VERSION 5.7 ;
  NAMESCASESENSITIVE ON ;
  NOWIREEXTENSIONATPIN ON ;
  DIVIDERCHAR "/" ;
  BUSBITCHARS "[]" ;
UNITS
  DATABASE MICRONS 200 ;
END UNITS

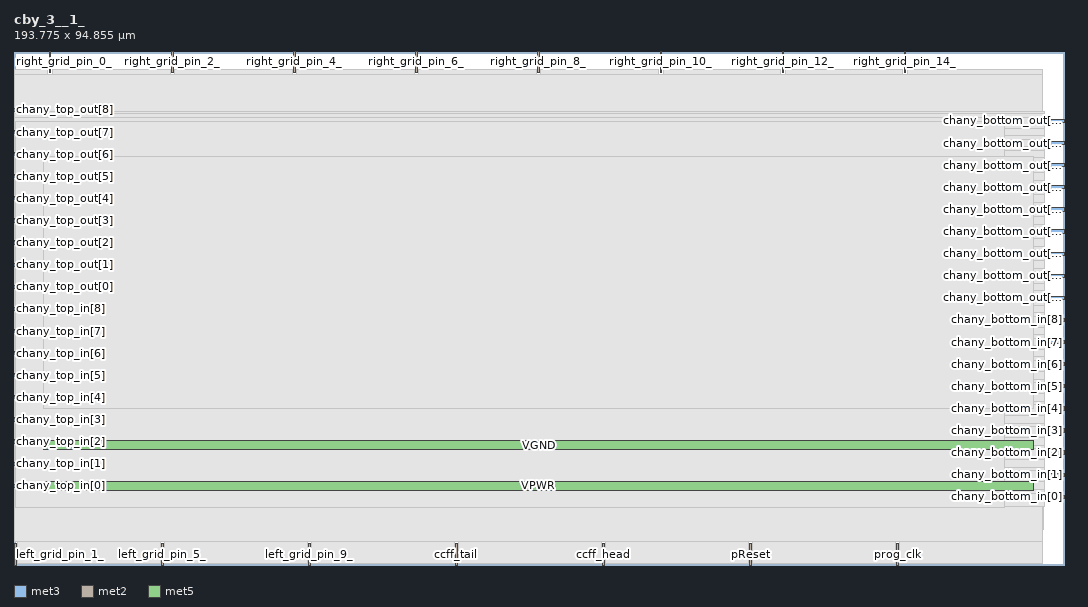
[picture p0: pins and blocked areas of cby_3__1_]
MACRO cby_3__1_
  CLASS BLOCK ;
  FOREIGN cby_3__1_ ;
  ORIGIN 0.000 0.000 ;
  SIZE 193.775 BY 94.855 ;
  PIN chany_top_in[0]
    DIRECTION INPUT ;
    PORT
      LAYER met3 ;
        RECT 0.000 14.320 4.000 14.920 ;
    END
  END chany_top_in[0]
  PIN chany_top_in[1]
    DIRECTION INPUT ;
    PORT
      LAYER met3 ;
        RECT 0.000 18.400 4.000 19.000 ;
    END
  END chany_top_in[1]
  PIN chany_top_in[2]
    DIRECTION INPUT ;
    PORT
      LAYER met3 ;
        RECT 0.000 22.480 4.000 23.080 ;
    END
  END chany_top_in[2]
  PIN chany_top_in[3]
    DIRECTION INPUT ;
    PORT
      LAYER met3 ;
        RECT 0.000 26.560 4.000 27.160 ;
    END
  END chany_top_in[3]
  PIN chany_top_in[4]
    DIRECTION INPUT ;
    PORT
      LAYER met3 ;
        RECT 0.000 30.640 4.000 31.240 ;
    END
  END chany_top_in[4]
  PIN chany_top_in[5]
    DIRECTION INPUT ;
    PORT
      LAYER met3 ;
        RECT 0.000 34.720 4.000 35.320 ;
    END
  END chany_top_in[5]
  PIN chany_top_in[6]
    DIRECTION INPUT ;
    PORT
      LAYER met3 ;
        RECT 0.000 38.800 4.000 39.400 ;
    END
  END chany_top_in[6]
  PIN chany_top_in[7]
    DIRECTION INPUT ;
    PORT
      LAYER met3 ;
        RECT 0.000 42.880 4.000 43.480 ;
    END
  END chany_top_in[7]
  PIN chany_top_in[8]
    DIRECTION INPUT ;
    PORT
      LAYER met3 ;
        RECT 0.000 46.960 4.000 47.560 ;
    END
  END chany_top_in[8]
  PIN chany_top_out[0]
    DIRECTION OUTPUT TRISTATE ;
    PORT
      LAYER met3 ;
        RECT 0.000 51.040 4.000 51.640 ;
    END
  END chany_top_out[0]
  PIN chany_top_out[1]
    DIRECTION OUTPUT TRISTATE ;
    PORT
      LAYER met3 ;
        RECT 0.000 55.120 4.000 55.720 ;
    END
  END chany_top_out[1]
  PIN chany_top_out[2]
    DIRECTION OUTPUT TRISTATE ;
    PORT
      LAYER met3 ;
        RECT 0.000 59.200 4.000 59.800 ;
    END
  END chany_top_out[2]
  PIN chany_top_out[3]
    DIRECTION OUTPUT TRISTATE ;
    PORT
      LAYER met3 ;
        RECT 0.000 63.280 4.000 63.880 ;
    END
  END chany_top_out[3]
  PIN chany_top_out[4]
    DIRECTION OUTPUT TRISTATE ;
    PORT
      LAYER met3 ;
        RECT 0.000 67.360 4.000 67.960 ;
    END
  END chany_top_out[4]
  PIN chany_top_out[5]
    DIRECTION OUTPUT TRISTATE ;
    PORT
      LAYER met3 ;
        RECT 0.000 71.440 4.000 72.040 ;
    END
  END chany_top_out[5]
  PIN chany_top_out[6]
    DIRECTION OUTPUT TRISTATE ;
    PORT
      LAYER met3 ;
        RECT 0.000 75.520 4.000 76.120 ;
    END
  END chany_top_out[6]
  PIN chany_top_out[7]
    DIRECTION OUTPUT TRISTATE ;
    PORT
      LAYER met3 ;
        RECT 0.000 79.600 4.000 80.200 ;
    END
  END chany_top_out[7]
  PIN chany_top_out[8]
    DIRECTION OUTPUT TRISTATE ;
    PORT
      LAYER met3 ;
        RECT 0.000 83.680 4.000 84.280 ;
    END
  END chany_top_out[8]
  PIN right_grid_pin_0_
    DIRECTION OUTPUT TRISTATE ;
    PORT
      LAYER met2 ;
        RECT 6.530 90.855 6.810 94.855 ;
    END
  END right_grid_pin_0_
  PIN right_grid_pin_2_
    DIRECTION OUTPUT TRISTATE ;
    PORT
      LAYER met2 ;
        RECT 29.070 90.855 29.350 94.855 ;
    END
  END right_grid_pin_2_
  PIN right_grid_pin_4_
    DIRECTION OUTPUT TRISTATE ;
    PORT
      LAYER met2 ;
        RECT 51.610 90.855 51.890 94.855 ;
    END
  END right_grid_pin_4_
  PIN right_grid_pin_6_
    DIRECTION OUTPUT TRISTATE ;
    PORT
      LAYER met2 ;
        RECT 74.150 90.855 74.430 94.855 ;
    END
  END right_grid_pin_6_
  PIN right_grid_pin_8_
    DIRECTION OUTPUT TRISTATE ;
    PORT
      LAYER met2 ;
        RECT 96.690 90.855 96.970 94.855 ;
    END
  END right_grid_pin_8_
  PIN right_grid_pin_10_
    DIRECTION OUTPUT TRISTATE ;
    PORT
      LAYER met2 ;
        RECT 119.230 90.855 119.510 94.855 ;
    END
  END right_grid_pin_10_
  PIN right_grid_pin_12_
    DIRECTION OUTPUT TRISTATE ;
    PORT
      LAYER met2 ;
        RECT 141.770 90.855 142.050 94.855 ;
    END
  END right_grid_pin_12_
  PIN right_grid_pin_14_
    DIRECTION OUTPUT TRISTATE ;
    PORT
      LAYER met2 ;
        RECT 164.310 90.855 164.590 94.855 ;
    END
  END right_grid_pin_14_
  PIN chany_bottom_in[0]
    DIRECTION INPUT ;
    PORT
      LAYER met3 ;
        RECT 189.775 12.280 193.775 12.880 ;
    END
  END chany_bottom_in[0]
  PIN chany_bottom_in[1]
    DIRECTION INPUT ;
    PORT
      LAYER met3 ;
        RECT 189.775 16.360 193.775 16.960 ;
    END
  END chany_bottom_in[1]
  PIN chany_bottom_in[2]
    DIRECTION INPUT ;
    PORT
      LAYER met3 ;
        RECT 189.775 20.440 193.775 21.040 ;
    END
  END chany_bottom_in[2]
  PIN chany_bottom_in[3]
    DIRECTION INPUT ;
    PORT
      LAYER met3 ;
        RECT 189.775 24.520 193.775 25.120 ;
    END
  END chany_bottom_in[3]
  PIN chany_bottom_in[4]
    DIRECTION INPUT ;
    PORT
      LAYER met3 ;
        RECT 189.775 28.600 193.775 29.200 ;
    END
  END chany_bottom_in[4]
  PIN chany_bottom_in[5]
    DIRECTION INPUT ;
    PORT
      LAYER met3 ;
        RECT 189.775 32.680 193.775 33.280 ;
    END
  END chany_bottom_in[5]
  PIN chany_bottom_in[6]
    DIRECTION INPUT ;
    PORT
      LAYER met3 ;
        RECT 189.775 36.760 193.775 37.360 ;
    END
  END chany_bottom_in[6]
  PIN chany_bottom_in[7]
    DIRECTION INPUT ;
    PORT
      LAYER met3 ;
        RECT 189.775 40.840 193.775 41.440 ;
    END
  END chany_bottom_in[7]
  PIN chany_bottom_in[8]
    DIRECTION INPUT ;
    PORT
      LAYER met3 ;
        RECT 189.775 44.920 193.775 45.520 ;
    END
  END chany_bottom_in[8]
  PIN chany_bottom_out[0]
    DIRECTION OUTPUT TRISTATE ;
    PORT
      LAYER met3 ;
        RECT 189.775 49.000 193.775 49.600 ;
    END
  END chany_bottom_out[0]
  PIN chany_bottom_out[1]
    DIRECTION OUTPUT TRISTATE ;
    PORT
      LAYER met3 ;
        RECT 189.775 53.080 193.775 53.680 ;
    END
  END chany_bottom_out[1]
  PIN chany_bottom_out[2]
    DIRECTION OUTPUT TRISTATE ;
    PORT
      LAYER met3 ;
        RECT 189.775 57.160 193.775 57.760 ;
    END
  END chany_bottom_out[2]
  PIN chany_bottom_out[3]
    DIRECTION OUTPUT TRISTATE ;
    PORT
      LAYER met3 ;
        RECT 189.775 61.240 193.775 61.840 ;
    END
  END chany_bottom_out[3]
  PIN chany_bottom_out[4]
    DIRECTION OUTPUT TRISTATE ;
    PORT
      LAYER met3 ;
        RECT 189.775 65.320 193.775 65.920 ;
    END
  END chany_bottom_out[4]
  PIN chany_bottom_out[5]
    DIRECTION OUTPUT TRISTATE ;
    PORT
      LAYER met3 ;
        RECT 189.775 69.400 193.775 70.000 ;
    END
  END chany_bottom_out[5]
  PIN chany_bottom_out[6]
    DIRECTION OUTPUT TRISTATE ;
    PORT
      LAYER met3 ;
        RECT 189.775 73.480 193.775 74.080 ;
    END
  END chany_bottom_out[6]
  PIN chany_bottom_out[7]
    DIRECTION OUTPUT TRISTATE ;
    PORT
      LAYER met3 ;
        RECT 189.775 77.560 193.775 78.160 ;
    END
  END chany_bottom_out[7]
  PIN chany_bottom_out[8]
    DIRECTION OUTPUT TRISTATE ;
    PORT
      LAYER met3 ;
        RECT 189.775 81.640 193.775 82.240 ;
    END
  END chany_bottom_out[8]
  PIN left_grid_pin_1_
    DIRECTION OUTPUT TRISTATE ;
    PORT
      LAYER met2 ;
        RECT 0.090 0.000 0.370 4.000 ;
    END
  END left_grid_pin_1_
  PIN left_grid_pin_5_
    DIRECTION OUTPUT TRISTATE ;
    PORT
      LAYER met2 ;
        RECT 27.230 0.000 27.510 4.000 ;
    END
  END left_grid_pin_5_
  PIN left_grid_pin_9_
    DIRECTION OUTPUT TRISTATE ;
    PORT
      LAYER met2 ;
        RECT 54.370 0.000 54.650 4.000 ;
    END
  END left_grid_pin_9_
  PIN ccff_tail
    DIRECTION OUTPUT TRISTATE ;
    PORT
      LAYER met2 ;
        RECT 81.510 0.000 81.790 4.000 ;
    END
  END ccff_tail
  PIN ccff_head
    DIRECTION INPUT ;
    PORT
      LAYER met2 ;
        RECT 108.650 0.000 108.930 4.000 ;
    END
  END ccff_head
  PIN pReset
    DIRECTION INPUT ;
    PORT
      LAYER met2 ;
        RECT 135.790 0.000 136.070 4.000 ;
    END
  END pReset
  PIN prog_clk
    DIRECTION INPUT ;
    PORT
      LAYER met2 ;
        RECT 162.930 0.000 163.210 4.000 ;
    END
  END prog_clk
  PIN VPWR
    DIRECTION INPUT ;
    USE POWER ;
    PORT
      LAYER met5 ;
        RECT 5.520 13.840 188.140 15.440 ;
    END
  END VPWR
  PIN VGND
    DIRECTION INPUT ;
    USE GROUND ;
    PORT
      LAYER met5 ;
        RECT 5.520 21.340 188.140 22.940 ;
    END
  END VGND
  OBS
      LAYER li1 ;
        RECT 5.520 10.795 188.140 81.685 ;
      LAYER met1 ;
        RECT 0.530 6.500 189.910 81.840 ;
      LAYER met2 ;
        RECT 0.090 90.575 6.250 91.530 ;
        RECT 7.090 90.575 28.790 91.530 ;
        RECT 29.630 90.575 51.330 91.530 ;
        RECT 52.170 90.575 73.870 91.530 ;
        RECT 74.710 90.575 96.410 91.530 ;
        RECT 97.250 90.575 118.950 91.530 ;
        RECT 119.790 90.575 141.490 91.530 ;
        RECT 142.330 90.575 164.030 91.530 ;
        RECT 164.870 90.575 189.890 91.530 ;
        RECT 0.090 4.280 189.890 90.575 ;
        RECT 0.650 0.270 26.950 4.280 ;
        RECT 27.790 0.270 54.090 4.280 ;
        RECT 54.930 0.270 81.230 4.280 ;
        RECT 82.070 0.270 108.370 4.280 ;
        RECT 109.210 0.270 135.510 4.280 ;
        RECT 136.350 0.270 162.650 4.280 ;
        RECT 163.490 0.270 189.890 4.280 ;
      LAYER met3 ;
        RECT 4.400 83.280 190.130 83.680 ;
        RECT 0.065 82.640 190.130 83.280 ;
        RECT 0.065 81.240 189.375 82.640 ;
        RECT 0.065 80.600 190.130 81.240 ;
        RECT 4.400 79.200 190.130 80.600 ;
        RECT 0.065 78.560 190.130 79.200 ;
        RECT 0.065 77.160 189.375 78.560 ;
        RECT 0.065 76.520 190.130 77.160 ;
        RECT 4.400 75.120 190.130 76.520 ;
        RECT 0.065 74.480 190.130 75.120 ;
        RECT 0.065 73.080 189.375 74.480 ;
        RECT 0.065 72.440 190.130 73.080 ;
        RECT 4.400 71.040 190.130 72.440 ;
        RECT 0.065 70.400 190.130 71.040 ;
        RECT 0.065 69.000 189.375 70.400 ;
        RECT 0.065 68.360 190.130 69.000 ;
        RECT 4.400 66.960 190.130 68.360 ;
        RECT 0.065 66.320 190.130 66.960 ;
        RECT 0.065 64.920 189.375 66.320 ;
        RECT 0.065 64.280 190.130 64.920 ;
        RECT 4.400 62.880 190.130 64.280 ;
        RECT 0.065 62.240 190.130 62.880 ;
        RECT 0.065 60.840 189.375 62.240 ;
        RECT 0.065 60.200 190.130 60.840 ;
        RECT 4.400 58.800 190.130 60.200 ;
        RECT 0.065 58.160 190.130 58.800 ;
        RECT 0.065 56.760 189.375 58.160 ;
        RECT 0.065 56.120 190.130 56.760 ;
        RECT 4.400 54.720 190.130 56.120 ;
        RECT 0.065 54.080 190.130 54.720 ;
        RECT 0.065 52.680 189.375 54.080 ;
        RECT 0.065 52.040 190.130 52.680 ;
        RECT 4.400 50.640 190.130 52.040 ;
        RECT 0.065 50.000 190.130 50.640 ;
        RECT 0.065 48.600 189.375 50.000 ;
        RECT 0.065 47.960 190.130 48.600 ;
        RECT 4.400 46.560 190.130 47.960 ;
        RECT 0.065 45.920 190.130 46.560 ;
        RECT 0.065 44.520 189.375 45.920 ;
        RECT 0.065 43.880 190.130 44.520 ;
        RECT 4.400 42.480 190.130 43.880 ;
        RECT 0.065 41.840 190.130 42.480 ;
        RECT 0.065 40.440 189.375 41.840 ;
        RECT 0.065 39.800 190.130 40.440 ;
        RECT 4.400 38.400 190.130 39.800 ;
        RECT 0.065 37.760 190.130 38.400 ;
        RECT 0.065 36.360 189.375 37.760 ;
        RECT 0.065 35.720 190.130 36.360 ;
        RECT 4.400 34.320 190.130 35.720 ;
        RECT 0.065 33.680 190.130 34.320 ;
        RECT 0.065 32.280 189.375 33.680 ;
        RECT 0.065 31.640 190.130 32.280 ;
        RECT 4.400 30.240 190.130 31.640 ;
        RECT 0.065 29.600 190.130 30.240 ;
        RECT 0.065 28.200 189.375 29.600 ;
        RECT 0.065 27.560 190.130 28.200 ;
        RECT 4.400 26.160 190.130 27.560 ;
        RECT 0.065 25.520 190.130 26.160 ;
        RECT 0.065 24.120 189.375 25.520 ;
        RECT 0.065 23.480 190.130 24.120 ;
        RECT 4.400 22.080 190.130 23.480 ;
        RECT 0.065 21.440 190.130 22.080 ;
        RECT 0.065 20.040 189.375 21.440 ;
        RECT 0.065 19.400 190.130 20.040 ;
        RECT 4.400 18.000 190.130 19.400 ;
        RECT 0.065 17.360 190.130 18.000 ;
        RECT 0.065 15.960 189.375 17.360 ;
        RECT 0.065 15.320 190.130 15.960 ;
        RECT 4.400 13.920 190.130 15.320 ;
        RECT 0.065 13.280 190.130 13.920 ;
        RECT 0.065 11.880 189.375 13.280 ;
        RECT 0.065 10.715 190.130 11.880 ;
      LAYER met4 ;
        RECT 0.295 10.640 182.820 81.840 ;
      LAYER met5 ;
        RECT 5.520 28.840 188.140 75.440 ;
  END
END cby_3__1_
END LIBRARY

